VERSION 5.8 ;
BUSBITCHARS "[]" ;
DIVIDERCHAR "/" ;

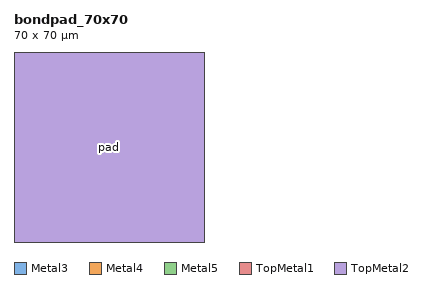
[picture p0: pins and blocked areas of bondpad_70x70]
MACRO bondpad_70x70
  CLASS COVER ;
  ORIGIN 0 0 ;
  FOREIGN bondpad_70x70 0 0 ;
  SIZE 70.0 BY 70.0 ;
  SYMMETRY X Y R90 ;
  PIN pad
    DIRECTION INOUT ;
    USE SIGNAL ;
    PORT
      LAYER Metal3 ;
        RECT 0 0 70.0 70.0 ;
      LAYER Metal4 ;
        RECT 0 0 70.0 70.0 ;
      LAYER Metal5 ;
        RECT 0 0 70.0 70.0 ;
      LAYER TopMetal1 ;
        RECT 0 0 70.0 70.0 ;
      LAYER TopMetal2 ;
        RECT 0 0 70.0 70.0 ;
    END
  END pad
END bondpad_70x70

END LIBRARY
